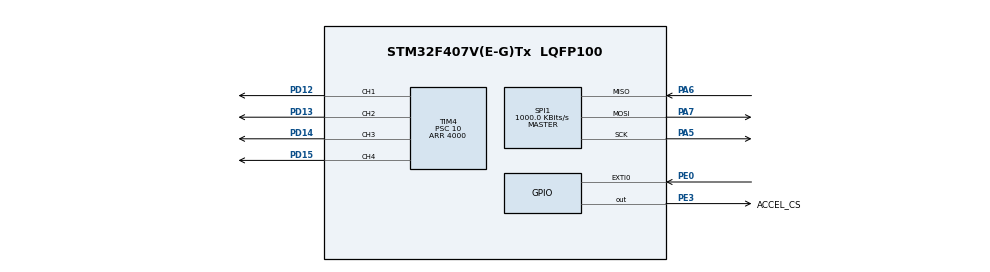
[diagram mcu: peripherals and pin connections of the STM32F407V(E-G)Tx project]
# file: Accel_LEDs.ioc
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Mcu.Family=STM32F4
Mcu.Name=STM32F407V(E-G)Tx
Mcu.Package=LQFP100
NVIC.PriorityGroup=NVIC_PRIORITYGROUP_0
PA5.Mode=Full_Duplex_Master
PA5.Signal=SPI1_SCK
PA6.Mode=Full_Duplex_Master
PA6.Signal=SPI1_MISO
PA7.Mode=Full_Duplex_Master
PA7.Signal=SPI1_MOSI
PD12.Signal=S_TIM4_CH1
PD13.Signal=S_TIM4_CH2
PD14.Signal=S_TIM4_CH3
PD15.Signal=S_TIM4_CH4
PE0.Signal=GPXTI0
PE3.GPIO_Label=ACCEL_CS
PE3.Signal=GPIO_Output
ProjectManager.HeapSize=0x200
ProjectManager.StackSize=0x400
ProjectManager.TargetToolchain=SW4STM32
RCC.48MHZClocksFreq_Value=14285714.285714285
RCC.AHBFreq_Value=16000000
RCC.APB1CLKDivider=RCC_HCLK_DIV16
RCC.APB1Freq_Value=1000000
RCC.APB1TimFreq_Value=2000000
RCC.APB2CLKDivider=RCC_HCLK_DIV2
RCC.APB2Freq_Value=8000000
RCC.APB2TimFreq_Value=16000000
RCC.CortexFreq_Value=16000000
RCC.HCLKFreq_Value=16000000
RCC.HSE_VALUE=8000000
RCC.HSI_VALUE=16000000
RCC.LSE_VALUE=32768
RCC.PLLM=8
RCC.PLLN=50
RCC.PLLP=RCC_PLLP_DIV4
RCC.PLLQ=7
RCC.SYSCLKFreq_VALUE=16000000
RCC.VCOOutputFreq_Value=100000000
SH.S_TIM4_CH1.0=TIM4_CH1,PWM Generation1 CH1
SH.S_TIM4_CH2.0=TIM4_CH2,PWM Generation2 CH2
SH.S_TIM4_CH3.0=TIM4_CH3,PWM Generation3 CH3
SH.S_TIM4_CH4.0=TIM4_CH4,PWM Generation4 CH4
SPI1.BaudRatePrescaler=SPI_BAUDRATEPRESCALER_8
SPI1.CalculateBaudRate=1000.0 KBits/s
SPI1.Direction=SPI_DIRECTION_2LINES
SPI1.Mode=SPI_MODE_MASTER
SPI1.VirtualType=VM_MASTER
TIM4.Channel-PWM\ Generation1\ CH1=TIM_CHANNEL_1
TIM4.Channel-PWM\ Generation2\ CH2=TIM_CHANNEL_2
TIM4.Channel-PWM\ Generation3\ CH3=TIM_CHANNEL_3
TIM4.Channel-PWM\ Generation4\ CH4=TIM_CHANNEL_4
TIM4.Period=4000
TIM4.Prescaler=10
VP_TIM4_VS_ClockSourceINT.Mode=Internal
board=STM32F407G-DISC1

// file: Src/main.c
/**
  ******************************************************************************
  * @file           : main.c
  * @brief          : Main control loop
  ******************************************************************************
  * @attention
  *
  * <h2><center>&copy; Copyright (c) 2019 STMicroelectronics.
  * All rights reserved.</center></h2>
  *
  * This software component is licensed by ST under BSD 3-Clause license,
  * the "License"; You may not use this file except in compliance with the
  * License. You may obtain a copy of the License at:
  *                        opensource.org/licenses/BSD-3-Clause
  *
  ******************************************************************************
  */

#include <stdio.h>
#include "main.h"
#include "utils.h"
#include "drone.h"

LIS3DSH_DataScaled accelData;
UART_HandleTypeDef huart2;
uint accel_flag = 0;

SPI_HandleTypeDef hspi1;

TIM_HandleTypeDef htim4;

void SystemClock_Config(void);
void UART_Config(void);
void init_motors(void);
static void MX_GPIO_Init(void);
static void MX_SPI1_Init(void);
static void MX_TIM4_Init(void);
void config_accel(void);
void config_control_params(void);
void EXTI0_IRQHandler(void);

int16_t txData[4];
int16_t throttle = 0;
LIS3DSH_InitTypeDef accelConfigDef;
DroneInitStruct droneInitStruct;
DroneInputStruct droneInputStruct;

int main(void)
{
  SystemClock_Config();
  MX_GPIO_Init();
  HAL_Init();
  config_accel();
  config_control_params();
  UART_Config();
  MX_SPI1_Init();
  MX_TIM4_Init();
  LIS3DSH_Init(&hspi1, &accelConfigDef);
  HAL_TIM_PWM_Start(&htim4, TIM_CHANNEL_1);
  HAL_TIM_PWM_Start(&htim4, TIM_CHANNEL_2);
  HAL_TIM_PWM_Start(&htim4, TIM_CHANNEL_3);
  HAL_TIM_PWM_Start(&htim4, TIM_CHANNEL_4);
  init_motors();

  set_input(0, 0, 0);

  while (1) {
    if (accel_flag == 1) {
      accel_flag = 0;
      calculate_PID(LIS3DSH_GetDataScaled());
      set_input(0, 0, throttle);
      set_motors(&htim4);

//      txData[0] = controller.xp;
//      txData[1] = controller.xi;
//      txData[2] = controller.xd;
//
//      HAL_UART_Transmit(&huart2, (uint8_t *) txData, sizeof txData, 10);
    }

    // Slowly ramp up throttle
    if(throttle < 3000){
      throttle += .01;
    }

    HAL_NVIC_EnableIRQ(EXTI0_IRQn);
  }
}

void EXTI0_IRQHandler(void)
{
  HAL_NVIC_DisableIRQ(EXTI0_IRQn);
  accel_flag = 1;
  return;
}

void config_accel(void){
  accelConfigDef.dataRate = LIS3DSH_DATARATE_400;
  accelConfigDef.fullScale = LIS3DSH_FULLSCALE_4;
  accelConfigDef.antiAliasingBW = LIS3DSH_FILTER_BW_50;
  accelConfigDef.enableAxes = LIS3DSH_XYZ_ENABLE;
  accelConfigDef.interruptEnable = true;
}

void config_control_params(void){
  droneInitStruct.p_gain = 1;
  droneInitStruct.i_gain = .01;
  droneInitStruct.d_gain = 15;

  droneInitStruct.filter_mode = FILTER_MODE_ELIMINATE_OUTLIERS;

  drone_init(&droneInitStruct);
}

void SystemClock_Config(void)
{
  RCC_OscInitTypeDef RCC_OscInitStruct = {0};
  RCC_ClkInitTypeDef RCC_ClkInitStruct = {0};

  /** Configure the main internal regulator output voltage
  */
  __HAL_RCC_PWR_CLK_ENABLE();
  __HAL_PWR_VOLTAGESCALING_CONFIG(PWR_REGULATOR_VOLTAGE_SCALE1);
  /** Initializes the CPU, AHB and APB busses clocks
  */
  RCC_OscInitStruct.OscillatorType = RCC_OSCILLATORTYPE_HSI;
  RCC_OscInitStruct.HSIState = RCC_HSI_ON;
  RCC_OscInitStruct.HSICalibrationValue = RCC_HSICALIBRATION_DEFAULT;
  RCC_OscInitStruct.PLL.PLLState = RCC_PLL_ON;
  RCC_OscInitStruct.PLL.PLLSource = RCC_PLLSOURCE_HSI;
  RCC_OscInitStruct.PLL.PLLM = 8;
  RCC_OscInitStruct.PLL.PLLN = 50;
  RCC_OscInitStruct.PLL.PLLP = RCC_PLLP_DIV4;
  RCC_OscInitStruct.PLL.PLLQ = 7;
  if (HAL_RCC_OscConfig(&RCC_OscInitStruct) != HAL_OK)
  {
    Error_Handler();
  }
  /** Initializes the CPU, AHB an  // Error increasing, positive slope
  //  Slow down motors
  // Error increasing negative slope
  //  Speed up motorsd APB busses clocks
  */
  RCC_ClkInitStruct.ClockType = RCC_CLOCKTYPE_HCLK|RCC_CLOCKTYPE_SYSCLK
                              |RCC_CLOCKTYPE_PCLK1|RCC_CLOCKTYPE_PCLK2;
  RCC_ClkInitStruct.SYSCLKSource = RCC_SYSCLKSOURCE_PLLCLK;
  RCC_ClkInitStruct.AHBCLKDivider = RCC_SYSCLK_DIV1;
  RCC_ClkInitStruct.APB1CLKDivider = RCC_HCLK_DIV4;
  RCC_ClkInitStruct.APB2CLKDivider = RCC_HCLK_DIV2;

  if (HAL_RCC_ClockConfig(&RCC_ClkInitStruct, FLASH_LATENCY_0) != HAL_OK)
  {
    Error_Handler();
  }
}

static void MX_SPI1_Init(void)
{
  hspi1.Instance = SPI1;
  hspi1.Init.Mode = SPI_MODE_MASTER;
  hspi1.Init.Direction = SPI_DIRECTION_2LINES;
  hspi1.Init.DataSize = SPI_DATASIZE_8BIT;
  hspi1.Init.CLKPolarity = SPI_POLARITY_LOW;
  hspi1.Init.CLKPhase = SPI_PHASE_1EDGE;
  hspi1.Init.NSS = SPI_NSS_SOFT;
  hspi1.Init.BaudRatePrescaler = SPI_BAUDRATEPRESCALER_8;
  hspi1.Init.FirstBit = SPI_FIRSTBIT_MSB;
  hspi1.Init.TIMode = SPI_TIMODE_DISABLE;
  hspi1.Init.CRCCalculation = SPI_CRCCALCULATION_DISABLE;
  hspi1.Init.CRCPolynomial = 10;
  if (HAL_SPI_Init(&hspi1) != HAL_OK)
  {
    Error_Handler();
  }
}

static void MX_TIM4_Init(void)
{
  TIM_ClockConfigTypeDef sClockSourceConfig = {0};
  TIM_MasterConfigTypeDef sMasterConfig = {0};
  TIM_OC_InitTypeDef sConfigOC = {0};

  htim4.Instance = TIM4;
  htim4.Init.Prescaler = 67;
  htim4.Init.CounterMode = TIM_COUNTERMODE_UP;
  htim4.Init.Period = 3650;
  htim4.Init.ClockDivision = TIM_CLOCKDIVISION_DIV1;
  htim4.Init.AutoReloadPreload = TIM_AUTORELOAD_PRELOAD_DISABLE;
  if (HAL_TIM_Base_Init(&htim4) != HAL_OK)
  {
    Error_Handler();
  }
  sClockSourceConfig.ClockSource = TIM_CLOCKSOURCE_INTERNAL;
  if (HAL_TIM_ConfigClockSource(&htim4, &sClockSourceConfig) != HAL_OK)
  {
    Error_Handler();
  }
  if (HAL_TIM_PWM_Init(&htim4) != HAL_OK)
  {
    Error_Handler();
  }
  sMasterConfig.MasterOutputTrigger = TIM_TRGO_RESET;
  sMasterConfig.MasterSlaveMode = TIM_MASTERSLAVEMODE_DISABLE;
  if (HAL_TIMEx_MasterConfigSynchronization(&htim4, &sMasterConfig) != HAL_OK)
  {
    Error_Handler();
  }
  sConfigOC.OCMode = TIM_OCMODE_PWM1;
  sConfigOC.Pulse = 0;
  sConfigOC.OCPolarity = TIM_OCPOLARITY_HIGH;
  sConfigOC.OCFastMode = TIM_OCFAST_DISABLE;
  if (HAL_TIM_PWM_ConfigChannel(&htim4, &sConfigOC, TIM_CHANNEL_1) != HAL_OK)
  {
    Error_Handler();
  }
  if (HAL_TIM_PWM_ConfigChannel(&htim4, &sConfigOC, TIM_CHANNEL_2) != HAL_OK)
  {
    Error_Handler();
  }
  if (HAL_TIM_PWM_ConfigChannel(&htim4, &sConfigOC, TIM_CHANNEL_3) != HAL_OK)
  {
    Error_Handler();
  }
  if (HAL_TIM_PWM_ConfigChannel(&htim4, &sConfigOC, TIM_CHANNEL_4) != HAL_OK)
  {
    Error_Handler();
  }
  HAL_TIM_MspPostInit(&htim4);

}

static void MX_GPIO_Init(void)
{
  GPIO_InitTypeDef GPIO_InitStruct = {0};

  /* GPIO Ports Clock Enable */
  __HAL_RCC_GPIOE_CLK_ENABLE();
  __HAL_RCC_GPIOA_CLK_ENABLE();
  __HAL_RCC_GPIOD_CLK_ENABLE();

  /*Configure GPIO pin Output Level */
  HAL_GPIO_WritePin(ACCEL_CS_GPIO_Port, ACCEL_CS_Pin, GPIO_PIN_RESET);

  /*Configure GPIO pin : ACCEL_CS_Pin */
  GPIO_InitStruct.Pin = ACCEL_CS_Pin;
  GPIO_InitStruct.Mode = GPIO_MODE_OUTPUT_PP;
  GPIO_InitStruct.Pull = GPIO_NOPULL;
  GPIO_InitStruct.Speed = GPIO_SPEED_FREQ_LOW;
  HAL_GPIO_Init(ACCEL_CS_GPIO_Port, &GPIO_InitStruct);

  /*Configure GPIO pin : PE0 */
  GPIO_InitStruct.Pin = GPIO_PIN_0;
  GPIO_InitStruct.Mode = GPIO_MODE_IT_RISING;
  GPIO_InitStruct.Pull = GPIO_NOPULL;
  HAL_GPIO_Init(GPIOE, &GPIO_InitStruct);

  /*Configure GPIO pin : PA0 */
  GPIO_InitStruct.Pin = GPIO_PIN_0;
  GPIO_InitStruct.Mode = GPIO_MODE_INPUT;
  GPIO_InitStruct.Pull = GPIO_PIN_RESET;
  HAL_GPIO_Init(GPIOA, &GPIO_InitStruct);

  HAL_NVIC_EnableIRQ(EXTI0_IRQn);
}

void calibrate_accel(void)
{
  float min_x, min_y = 0, max_x , max_y;
  if (LIS3DSH_PollDRDY(1000) == true) {
    accelData = LIS3DSH_GetDataScaled();
    min_x = accelData.x;
    max_x = accelData.x;
    min_y = accelData.y;
    max_y = accelData.y;
  }
  while(HAL_GPIO_ReadPin(GPIOA, GPIO_PIN_0) == GPIO_PIN_RESET){
    if (LIS3DSH_PollDRDY(1000) == true) {
      accelData = LIS3DSH_GetDataScaled();
      if(accelData.x < min_x){
        min_x = accelData.x;
      }
      if(accelData.y < min_y){
        min_y = accelData.y;
      }
      if(accelData.x > min_x){
        max_x = accelData.x;
      }
      if(accelData.y > min_y){
        max_y = accelData.y;
      }
    }
  }
  LIS3DSH_X_calibrate(min_x, max_x);
  LIS3DSH_Y_calibrate(min_y, max_y);
  HAL_Delay(50);
}

void init_motors(void)
{
  if(HAL_GPIO_ReadPin(GPIOA, GPIO_PIN_0) == GPIO_PIN_SET){
    htim4.Instance->CCR1 = MAX_THROTTLE;
    htim4.Instance->CCR2 = MAX_THROTTLE;
    htim4.Instance->CCR3 = MAX_THROTTLE;
    htim4.Instance->CCR4 = MAX_THROTTLE;
    HAL_Delay(10000);
  }
  htim4.Instance->CCR1 = MIN_THROTTLE;
  htim4.Instance->CCR2 = MIN_THROTTLE;
  htim4.Instance->CCR3 = MIN_THROTTLE;
  htim4.Instance->CCR4 = MIN_THROTTLE;
  while(HAL_GPIO_ReadPin(GPIOA, GPIO_PIN_0) == GPIO_PIN_RESET){
    HAL_Delay(50);
  }
}

void UART_Config(void){
  __HAL_RCC_GPIOA_CLK_ENABLE();

  huart2.Instance = USART2;
  huart2.Init.BaudRate = 115200;
  huart2.Init.WordLength = UART_WORDLENGTH_8B;
  huart2.Init.StopBits = UART_STOPBITS_1;
  huart2.Init.Parity = UART_PARITY_NONE;
  huart2.Init.Mode = UART_MODE_TX_RX;
  huart2.Init.HwFlowCtl = UART_HWCONTROL_NONE;
  huart2.Init.OverSampling = UART_OVERSAMPLING_16;
  if (HAL_UART_Init(&huart2) != HAL_OK)
  {
    Error_Handler();
  }
}

void Error_Handler(void)
{
}

/************************ (C) COPYRIGHT STMicroelectronics *****END OF FILE****/
